# Generated by FakeRAM 2.0
VERSION 5.7 ;
BUSBITCHARS "[]" ;
PROPERTYDEFINITIONS
  MACRO width INTEGER ;
  MACRO depth INTEGER ;
  MACRO banks INTEGER ;
END PROPERTYDEFINITIONS
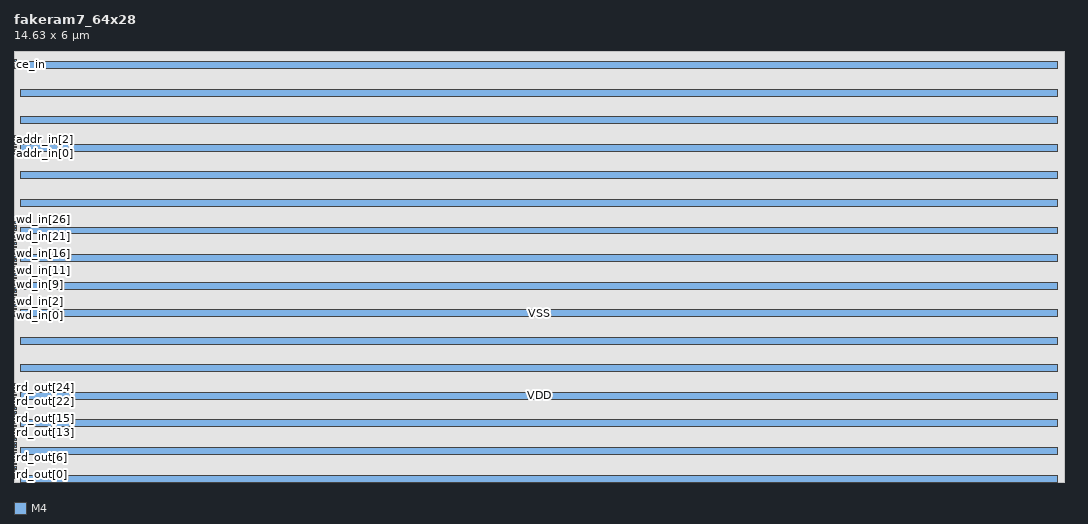
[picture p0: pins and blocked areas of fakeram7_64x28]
MACRO fakeram7_64x28
  PROPERTY width 28 ;
  PROPERTY depth 64 ;
  PROPERTY banks 4 ;
  FOREIGN fakeram7_64x28 0 0 ;
  SYMMETRY X Y R90 ;
  SIZE 14.630 BY 6.000 ;
  CLASS BLOCK ;
  PIN rd_out[0]
    DIRECTION OUTPUT ;
    USE SIGNAL ;
    SHAPE ABUTMENT ;
    PORT
      LAYER M4 ;
      RECT 0.000 0.048 0.036 0.072 ;
    END
  END rd_out[0]
  PIN rd_out[1]
    DIRECTION OUTPUT ;
    USE SIGNAL ;
    SHAPE ABUTMENT ;
    PORT
      LAYER M4 ;
      RECT 0.000 0.096 0.036 0.120 ;
    END
  END rd_out[1]
  PIN rd_out[2]
    DIRECTION OUTPUT ;
    USE SIGNAL ;
    SHAPE ABUTMENT ;
    PORT
      LAYER M4 ;
      RECT 0.000 0.144 0.036 0.168 ;
    END
  END rd_out[2]
  PIN rd_out[3]
    DIRECTION OUTPUT ;
    USE SIGNAL ;
    SHAPE ABUTMENT ;
    PORT
      LAYER M4 ;
      RECT 0.000 0.192 0.036 0.216 ;
    END
  END rd_out[3]
  PIN rd_out[4]
    DIRECTION OUTPUT ;
    USE SIGNAL ;
    SHAPE ABUTMENT ;
    PORT
      LAYER M4 ;
      RECT 0.000 0.240 0.036 0.264 ;
    END
  END rd_out[4]
  PIN rd_out[5]
    DIRECTION OUTPUT ;
    USE SIGNAL ;
    SHAPE ABUTMENT ;
    PORT
      LAYER M4 ;
      RECT 0.000 0.288 0.036 0.312 ;
    END
  END rd_out[5]
  PIN rd_out[6]
    DIRECTION OUTPUT ;
    USE SIGNAL ;
    SHAPE ABUTMENT ;
    PORT
      LAYER M4 ;
      RECT 0.000 0.336 0.036 0.360 ;
    END
  END rd_out[6]
  PIN rd_out[7]
    DIRECTION OUTPUT ;
    USE SIGNAL ;
    SHAPE ABUTMENT ;
    PORT
      LAYER M4 ;
      RECT 0.000 0.384 0.036 0.408 ;
    END
  END rd_out[7]
  PIN rd_out[8]
    DIRECTION OUTPUT ;
    USE SIGNAL ;
    SHAPE ABUTMENT ;
    PORT
      LAYER M4 ;
      RECT 0.000 0.432 0.036 0.456 ;
    END
  END rd_out[8]
  PIN rd_out[9]
    DIRECTION OUTPUT ;
    USE SIGNAL ;
    SHAPE ABUTMENT ;
    PORT
      LAYER M4 ;
      RECT 0.000 0.480 0.036 0.504 ;
    END
  END rd_out[9]
  PIN rd_out[10]
    DIRECTION OUTPUT ;
    USE SIGNAL ;
    SHAPE ABUTMENT ;
    PORT
      LAYER M4 ;
      RECT 0.000 0.528 0.036 0.552 ;
    END
  END rd_out[10]
  PIN rd_out[11]
    DIRECTION OUTPUT ;
    USE SIGNAL ;
    SHAPE ABUTMENT ;
    PORT
      LAYER M4 ;
      RECT 0.000 0.576 0.036 0.600 ;
    END
  END rd_out[11]
  PIN rd_out[12]
    DIRECTION OUTPUT ;
    USE SIGNAL ;
    SHAPE ABUTMENT ;
    PORT
      LAYER M4 ;
      RECT 0.000 0.624 0.036 0.648 ;
    END
  END rd_out[12]
  PIN rd_out[13]
    DIRECTION OUTPUT ;
    USE SIGNAL ;
    SHAPE ABUTMENT ;
    PORT
      LAYER M4 ;
      RECT 0.000 0.672 0.036 0.696 ;
    END
  END rd_out[13]
  PIN rd_out[14]
    DIRECTION OUTPUT ;
    USE SIGNAL ;
    SHAPE ABUTMENT ;
    PORT
      LAYER M4 ;
      RECT 0.000 0.720 0.036 0.744 ;
    END
  END rd_out[14]
  PIN rd_out[15]
    DIRECTION OUTPUT ;
    USE SIGNAL ;
    SHAPE ABUTMENT ;
    PORT
      LAYER M4 ;
      RECT 0.000 0.768 0.036 0.792 ;
    END
  END rd_out[15]
  PIN rd_out[16]
    DIRECTION OUTPUT ;
    USE SIGNAL ;
    SHAPE ABUTMENT ;
    PORT
      LAYER M4 ;
      RECT 0.000 0.816 0.036 0.840 ;
    END
  END rd_out[16]
  PIN rd_out[17]
    DIRECTION OUTPUT ;
    USE SIGNAL ;
    SHAPE ABUTMENT ;
    PORT
      LAYER M4 ;
      RECT 0.000 0.864 0.036 0.888 ;
    END
  END rd_out[17]
  PIN rd_out[18]
    DIRECTION OUTPUT ;
    USE SIGNAL ;
    SHAPE ABUTMENT ;
    PORT
      LAYER M4 ;
      RECT 0.000 0.912 0.036 0.936 ;
    END
  END rd_out[18]
  PIN rd_out[19]
    DIRECTION OUTPUT ;
    USE SIGNAL ;
    SHAPE ABUTMENT ;
    PORT
      LAYER M4 ;
      RECT 0.000 0.960 0.036 0.984 ;
    END
  END rd_out[19]
  PIN rd_out[20]
    DIRECTION OUTPUT ;
    USE SIGNAL ;
    SHAPE ABUTMENT ;
    PORT
      LAYER M4 ;
      RECT 0.000 1.008 0.036 1.032 ;
    END
  END rd_out[20]
  PIN rd_out[21]
    DIRECTION OUTPUT ;
    USE SIGNAL ;
    SHAPE ABUTMENT ;
    PORT
      LAYER M4 ;
      RECT 0.000 1.056 0.036 1.080 ;
    END
  END rd_out[21]
  PIN rd_out[22]
    DIRECTION OUTPUT ;
    USE SIGNAL ;
    SHAPE ABUTMENT ;
    PORT
      LAYER M4 ;
      RECT 0.000 1.104 0.036 1.128 ;
    END
  END rd_out[22]
  PIN rd_out[23]
    DIRECTION OUTPUT ;
    USE SIGNAL ;
    SHAPE ABUTMENT ;
    PORT
      LAYER M4 ;
      RECT 0.000 1.152 0.036 1.176 ;
    END
  END rd_out[23]
  PIN rd_out[24]
    DIRECTION OUTPUT ;
    USE SIGNAL ;
    SHAPE ABUTMENT ;
    PORT
      LAYER M4 ;
      RECT 0.000 1.200 0.036 1.224 ;
    END
  END rd_out[24]
  PIN rd_out[25]
    DIRECTION OUTPUT ;
    USE SIGNAL ;
    SHAPE ABUTMENT ;
    PORT
      LAYER M4 ;
      RECT 0.000 1.248 0.036 1.272 ;
    END
  END rd_out[25]
  PIN rd_out[26]
    DIRECTION OUTPUT ;
    USE SIGNAL ;
    SHAPE ABUTMENT ;
    PORT
      LAYER M4 ;
      RECT 0.000 1.296 0.036 1.320 ;
    END
  END rd_out[26]
  PIN rd_out[27]
    DIRECTION OUTPUT ;
    USE SIGNAL ;
    SHAPE ABUTMENT ;
    PORT
      LAYER M4 ;
      RECT 0.000 1.344 0.036 1.368 ;
    END
  END rd_out[27]
  PIN wd_in[0]
    DIRECTION INPUT ;
    USE SIGNAL ;
    SHAPE ABUTMENT ;
    PORT
      LAYER M4 ;
      RECT 0.000 2.304 0.036 2.328 ;
    END
  END wd_in[0]
  PIN wd_in[1]
    DIRECTION INPUT ;
    USE SIGNAL ;
    SHAPE ABUTMENT ;
    PORT
      LAYER M4 ;
      RECT 0.000 2.352 0.036 2.376 ;
    END
  END wd_in[1]
  PIN wd_in[2]
    DIRECTION INPUT ;
    USE SIGNAL ;
    SHAPE ABUTMENT ;
    PORT
      LAYER M4 ;
      RECT 0.000 2.400 0.036 2.424 ;
    END
  END wd_in[2]
  PIN wd_in[3]
    DIRECTION INPUT ;
    USE SIGNAL ;
    SHAPE ABUTMENT ;
    PORT
      LAYER M4 ;
      RECT 0.000 2.448 0.036 2.472 ;
    END
  END wd_in[3]
  PIN wd_in[4]
    DIRECTION INPUT ;
    USE SIGNAL ;
    SHAPE ABUTMENT ;
    PORT
      LAYER M4 ;
      RECT 0.000 2.496 0.036 2.520 ;
    END
  END wd_in[4]
  PIN wd_in[5]
    DIRECTION INPUT ;
    USE SIGNAL ;
    SHAPE ABUTMENT ;
    PORT
      LAYER M4 ;
      RECT 0.000 2.544 0.036 2.568 ;
    END
  END wd_in[5]
  PIN wd_in[6]
    DIRECTION INPUT ;
    USE SIGNAL ;
    SHAPE ABUTMENT ;
    PORT
      LAYER M4 ;
      RECT 0.000 2.592 0.036 2.616 ;
    END
  END wd_in[6]
  PIN wd_in[7]
    DIRECTION INPUT ;
    USE SIGNAL ;
    SHAPE ABUTMENT ;
    PORT
      LAYER M4 ;
      RECT 0.000 2.640 0.036 2.664 ;
    END
  END wd_in[7]
  PIN wd_in[8]
    DIRECTION INPUT ;
    USE SIGNAL ;
    SHAPE ABUTMENT ;
    PORT
      LAYER M4 ;
      RECT 0.000 2.688 0.036 2.712 ;
    END
  END wd_in[8]
  PIN wd_in[9]
    DIRECTION INPUT ;
    USE SIGNAL ;
    SHAPE ABUTMENT ;
    PORT
      LAYER M4 ;
      RECT 0.000 2.736 0.036 2.760 ;
    END
  END wd_in[9]
  PIN wd_in[10]
    DIRECTION INPUT ;
    USE SIGNAL ;
    SHAPE ABUTMENT ;
    PORT
      LAYER M4 ;
      RECT 0.000 2.784 0.036 2.808 ;
    END
  END wd_in[10]
  PIN wd_in[11]
    DIRECTION INPUT ;
    USE SIGNAL ;
    SHAPE ABUTMENT ;
    PORT
      LAYER M4 ;
      RECT 0.000 2.832 0.036 2.856 ;
    END
  END wd_in[11]
  PIN wd_in[12]
    DIRECTION INPUT ;
    USE SIGNAL ;
    SHAPE ABUTMENT ;
    PORT
      LAYER M4 ;
      RECT 0.000 2.880 0.036 2.904 ;
    END
  END wd_in[12]
  PIN wd_in[13]
    DIRECTION INPUT ;
    USE SIGNAL ;
    SHAPE ABUTMENT ;
    PORT
      LAYER M4 ;
      RECT 0.000 2.928 0.036 2.952 ;
    END
  END wd_in[13]
  PIN wd_in[14]
    DIRECTION INPUT ;
    USE SIGNAL ;
    SHAPE ABUTMENT ;
    PORT
      LAYER M4 ;
      RECT 0.000 2.976 0.036 3.000 ;
    END
  END wd_in[14]
  PIN wd_in[15]
    DIRECTION INPUT ;
    USE SIGNAL ;
    SHAPE ABUTMENT ;
    PORT
      LAYER M4 ;
      RECT 0.000 3.024 0.036 3.048 ;
    END
  END wd_in[15]
  PIN wd_in[16]
    DIRECTION INPUT ;
    USE SIGNAL ;
    SHAPE ABUTMENT ;
    PORT
      LAYER M4 ;
      RECT 0.000 3.072 0.036 3.096 ;
    END
  END wd_in[16]
  PIN wd_in[17]
    DIRECTION INPUT ;
    USE SIGNAL ;
    SHAPE ABUTMENT ;
    PORT
      LAYER M4 ;
      RECT 0.000 3.120 0.036 3.144 ;
    END
  END wd_in[17]
  PIN wd_in[18]
    DIRECTION INPUT ;
    USE SIGNAL ;
    SHAPE ABUTMENT ;
    PORT
      LAYER M4 ;
      RECT 0.000 3.168 0.036 3.192 ;
    END
  END wd_in[18]
  PIN wd_in[19]
    DIRECTION INPUT ;
    USE SIGNAL ;
    SHAPE ABUTMENT ;
    PORT
      LAYER M4 ;
      RECT 0.000 3.216 0.036 3.240 ;
    END
  END wd_in[19]
  PIN wd_in[20]
    DIRECTION INPUT ;
    USE SIGNAL ;
    SHAPE ABUTMENT ;
    PORT
      LAYER M4 ;
      RECT 0.000 3.264 0.036 3.288 ;
    END
  END wd_in[20]
  PIN wd_in[21]
    DIRECTION INPUT ;
    USE SIGNAL ;
    SHAPE ABUTMENT ;
    PORT
      LAYER M4 ;
      RECT 0.000 3.312 0.036 3.336 ;
    END
  END wd_in[21]
  PIN wd_in[22]
    DIRECTION INPUT ;
    USE SIGNAL ;
    SHAPE ABUTMENT ;
    PORT
      LAYER M4 ;
      RECT 0.000 3.360 0.036 3.384 ;
    END
  END wd_in[22]
  PIN wd_in[23]
    DIRECTION INPUT ;
    USE SIGNAL ;
    SHAPE ABUTMENT ;
    PORT
      LAYER M4 ;
      RECT 0.000 3.408 0.036 3.432 ;
    END
  END wd_in[23]
  PIN wd_in[24]
    DIRECTION INPUT ;
    USE SIGNAL ;
    SHAPE ABUTMENT ;
    PORT
      LAYER M4 ;
      RECT 0.000 3.456 0.036 3.480 ;
    END
  END wd_in[24]
  PIN wd_in[25]
    DIRECTION INPUT ;
    USE SIGNAL ;
    SHAPE ABUTMENT ;
    PORT
      LAYER M4 ;
      RECT 0.000 3.504 0.036 3.528 ;
    END
  END wd_in[25]
  PIN wd_in[26]
    DIRECTION INPUT ;
    USE SIGNAL ;
    SHAPE ABUTMENT ;
    PORT
      LAYER M4 ;
      RECT 0.000 3.552 0.036 3.576 ;
    END
  END wd_in[26]
  PIN wd_in[27]
    DIRECTION INPUT ;
    USE SIGNAL ;
    SHAPE ABUTMENT ;
    PORT
      LAYER M4 ;
      RECT 0.000 3.600 0.036 3.624 ;
    END
  END wd_in[27]
  PIN addr_in[0]
    DIRECTION INPUT ;
    USE SIGNAL ;
    SHAPE ABUTMENT ;
    PORT
      LAYER M4 ;
      RECT 0.000 4.560 0.036 4.584 ;
    END
  END addr_in[0]
  PIN addr_in[1]
    DIRECTION INPUT ;
    USE SIGNAL ;
    SHAPE ABUTMENT ;
    PORT
      LAYER M4 ;
      RECT 0.000 4.608 0.036 4.632 ;
    END
  END addr_in[1]
  PIN addr_in[2]
    DIRECTION INPUT ;
    USE SIGNAL ;
    SHAPE ABUTMENT ;
    PORT
      LAYER M4 ;
      RECT 0.000 4.656 0.036 4.680 ;
    END
  END addr_in[2]
  PIN addr_in[3]
    DIRECTION INPUT ;
    USE SIGNAL ;
    SHAPE ABUTMENT ;
    PORT
      LAYER M4 ;
      RECT 0.000 4.704 0.036 4.728 ;
    END
  END addr_in[3]
  PIN addr_in[4]
    DIRECTION INPUT ;
    USE SIGNAL ;
    SHAPE ABUTMENT ;
    PORT
      LAYER M4 ;
      RECT 0.000 4.752 0.036 4.776 ;
    END
  END addr_in[4]
  PIN addr_in[5]
    DIRECTION INPUT ;
    USE SIGNAL ;
    SHAPE ABUTMENT ;
    PORT
      LAYER M4 ;
      RECT 0.000 4.800 0.036 4.824 ;
    END
  END addr_in[5]
  PIN we_in
    DIRECTION INPUT ;
    USE SIGNAL ;
    SHAPE ABUTMENT ;
    PORT
      LAYER M4 ;
      RECT 0.000 5.760 0.036 5.784 ;
    END
  END we_in
  PIN ce_in
    DIRECTION INPUT ;
    USE SIGNAL ;
    SHAPE ABUTMENT ;
    PORT
      LAYER M4 ;
      RECT 0.000 5.808 0.036 5.832 ;
    END
  END ce_in
  PIN clk
    DIRECTION INPUT ;
    USE SIGNAL ;
    SHAPE ABUTMENT ;
    PORT
      LAYER M4 ;
      RECT 0.000 5.856 0.036 5.880 ;
    END
  END clk
  PIN VSS
    DIRECTION INOUT ;
    USE GROUND ;
    PORT
      LAYER M4 ;
      RECT 0.096 0.000 14.534 0.096 ;
      RECT 0.096 0.768 14.534 0.864 ;
      RECT 0.096 1.536 14.534 1.632 ;
      RECT 0.096 2.304 14.534 2.400 ;
      RECT 0.096 3.072 14.534 3.168 ;
      RECT 0.096 3.840 14.534 3.936 ;
      RECT 0.096 4.608 14.534 4.704 ;
      RECT 0.096 5.376 14.534 5.472 ;
    END
  END VSS
  PIN VDD
    DIRECTION INOUT ;
    USE POWER ;
    PORT
      LAYER M4 ;
      RECT 0.096 0.384 14.534 0.480 ;
      RECT 0.096 1.152 14.534 1.248 ;
      RECT 0.096 1.920 14.534 2.016 ;
      RECT 0.096 2.688 14.534 2.784 ;
      RECT 0.096 3.456 14.534 3.552 ;
      RECT 0.096 4.224 14.534 4.320 ;
      RECT 0.096 4.992 14.534 5.088 ;
      RECT 0.096 5.760 14.534 5.856 ;
    END
  END VDD
  OBS
    LAYER M1 ;
    RECT 0 0 14.630 6.000 ;
    LAYER M2 ;
    RECT 0 0 14.630 6.000 ;
    LAYER M3 ;
    RECT 0 0 14.630 6.000 ;
    LAYER M4 ;
    RECT 0 0 14.630 6.000 ;
  END
END fakeram7_64x28

END LIBRARY
